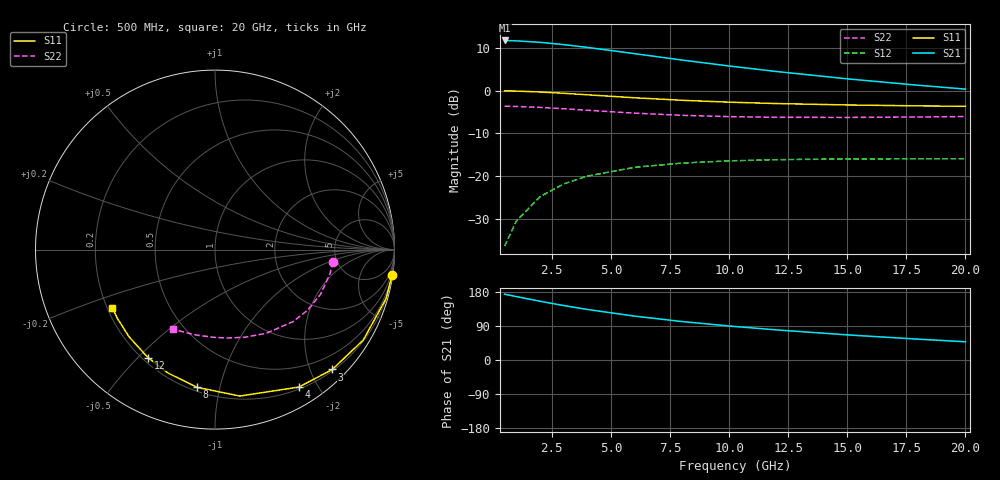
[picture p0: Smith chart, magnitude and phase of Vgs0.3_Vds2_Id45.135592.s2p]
# Hz S RI R 50
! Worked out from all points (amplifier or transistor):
!   12 points, 500 MHz to 20 GHz, reference 50 ohm
!   highest |S21| = 11.8 dB at 500 MHz (marker M1)
!   |S21| within 3 dB of that: start of sweep to 5.872 GHz
!   unconditionally stable (mu >= 1): 17.69 GHz to end of sweep
!   at 2 GHz: K = 0.11, MSG = 18.1 dB, |S12| = -24.8 dB
!   at 8 GHz: K = 0.44, MSG = 12.1 dB, |S12| = -16.9 dB
!   at 20 GHz: K = 1.15, MAG = 5.8 dB, |S12| = -15.9 dB
!   S11 on the Smith chart (normalised r, x): 500 MHz: 0, -14; 3 GHz: 0.22, -2.36; 4 GHz: 0.22, -1.76; 8 GHz: 0.22, -0.85; 12 GHz: 0.22, -0.54; 20 GHz: 0.22, -0.25
5e8  0.988 -0.1395  -3.861 0.4335  0.00144 0.015  0.6557 -0.0677
1e9  0.953 -0.2731  -3.749 0.848  0.00563 0.0294  0.6411 -0.133
2e9  0.8262 -0.5036  -3.346 1.559  0.0208 0.0536  0.5881 -0.249
3e9  0.6533 -0.6679  -2.798 2.057  0.0413 0.0697  0.5149 -0.3385
4e9  0.4676 -0.7657  -2.211 2.343  0.0632 0.0778  0.4347 -0.4011
6e9  0.1382 -0.816  -1.184 2.45  0.1011 0.0765  0.2857 -0.4664
8e9  -0.1009 -0.7671  -0.458 2.246  0.1272 0.0636  0.1661 -0.4883
1e10  -0.2633 -0.6865  0.0116 1.951  0.1433 0.0475  0.0718 -0.4923
1.2e10  -0.3737 -0.6017  0.3079 1.653  0.1526 0.0317  -0.00586 -0.4889
1.5e10  -0.4798 -0.4846  0.5545 1.263  0.1587 0.0107  -0.1033 -0.4763
1.8e10  -0.5439 -0.3832  0.6662 0.9497  0.1597 -0.00668  -0.1861 -0.4566
2e10  -0.5724 -0.3233  0.6981 0.779  0.1587 -0.0165  -0.2353 -0.4397
